VERSION 5.7 ;
BUSBITCHARS "[]" ;
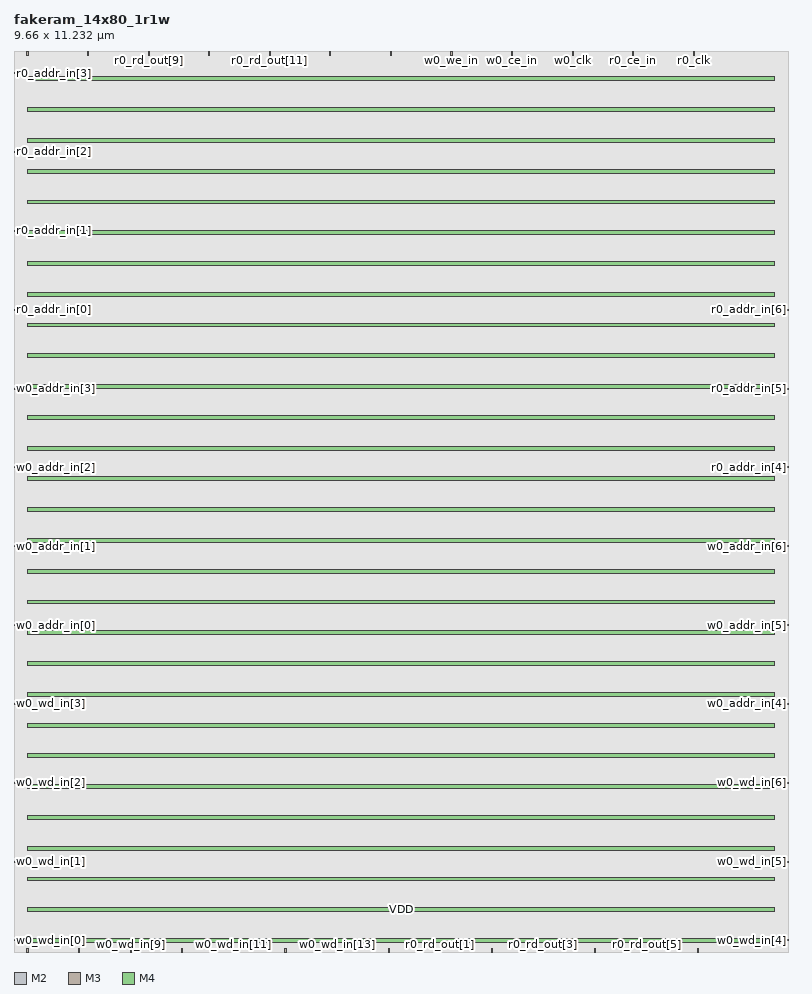
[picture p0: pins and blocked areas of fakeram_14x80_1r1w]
MACRO fakeram_14x80_1r1w
  FOREIGN fakeram_14x80_1r1w 0 0 ;
  SYMMETRY X Y R90 ;
  SIZE 9.660 BY 11.232 ;
  CLASS BLOCK ;
  PIN w0_wd_in[0]
    DIRECTION INPUT ;
    USE SIGNAL ;
    SHAPE ABUTMENT ;
    PORT
      LAYER M2 ;
      RECT 0.000 0.138 0.036 0.150 ;
    END
  END w0_wd_in[0]
  PIN w0_wd_in[1]
    DIRECTION INPUT ;
    USE SIGNAL ;
    SHAPE ABUTMENT ;
    PORT
      LAYER M2 ;
      RECT 0.000 1.122 0.036 1.134 ;
    END
  END w0_wd_in[1]
  PIN w0_wd_in[2]
    DIRECTION INPUT ;
    USE SIGNAL ;
    SHAPE ABUTMENT ;
    PORT
      LAYER M2 ;
      RECT 0.000 2.106 0.036 2.118 ;
    END
  END w0_wd_in[2]
  PIN w0_wd_in[3]
    DIRECTION INPUT ;
    USE SIGNAL ;
    SHAPE ABUTMENT ;
    PORT
      LAYER M2 ;
      RECT 0.000 3.090 0.036 3.102 ;
    END
  END w0_wd_in[3]
  PIN w0_wd_in[4]
    DIRECTION INPUT ;
    USE SIGNAL ;
    SHAPE ABUTMENT ;
    PORT
      LAYER M2 ;
      RECT 9.624 0.138 9.660 0.150 ;
    END
  END w0_wd_in[4]
  PIN w0_wd_in[5]
    DIRECTION INPUT ;
    USE SIGNAL ;
    SHAPE ABUTMENT ;
    PORT
      LAYER M2 ;
      RECT 9.624 1.122 9.660 1.134 ;
    END
  END w0_wd_in[5]
  PIN w0_wd_in[6]
    DIRECTION INPUT ;
    USE SIGNAL ;
    SHAPE ABUTMENT ;
    PORT
      LAYER M2 ;
      RECT 9.624 2.106 9.660 2.118 ;
    END
  END w0_wd_in[6]
  PIN w0_wd_in[7]
    DIRECTION INPUT ;
    USE SIGNAL ;
    SHAPE ABUTMENT ;
    PORT
      LAYER M3 ;
      RECT 0.161 0.000 0.175 0.042 ;
    END
  END w0_wd_in[7]
  PIN w0_wd_in[8]
    DIRECTION INPUT ;
    USE SIGNAL ;
    SHAPE ABUTMENT ;
    PORT
      LAYER M3 ;
      RECT 0.805 0.000 0.819 0.042 ;
    END
  END w0_wd_in[8]
  PIN w0_wd_in[9]
    DIRECTION INPUT ;
    USE SIGNAL ;
    SHAPE ABUTMENT ;
    PORT
      LAYER M3 ;
      RECT 1.449 0.000 1.463 0.042 ;
    END
  END w0_wd_in[9]
  PIN w0_wd_in[10]
    DIRECTION INPUT ;
    USE SIGNAL ;
    SHAPE ABUTMENT ;
    PORT
      LAYER M3 ;
      RECT 2.093 0.000 2.107 0.042 ;
    END
  END w0_wd_in[10]
  PIN w0_wd_in[11]
    DIRECTION INPUT ;
    USE SIGNAL ;
    SHAPE ABUTMENT ;
    PORT
      LAYER M3 ;
      RECT 2.737 0.000 2.751 0.042 ;
    END
  END w0_wd_in[11]
  PIN w0_wd_in[12]
    DIRECTION INPUT ;
    USE SIGNAL ;
    SHAPE ABUTMENT ;
    PORT
      LAYER M3 ;
      RECT 3.381 0.000 3.395 0.042 ;
    END
  END w0_wd_in[12]
  PIN w0_wd_in[13]
    DIRECTION INPUT ;
    USE SIGNAL ;
    SHAPE ABUTMENT ;
    PORT
      LAYER M3 ;
      RECT 4.025 0.000 4.039 0.042 ;
    END
  END w0_wd_in[13]
  PIN r0_rd_out[0]
    DIRECTION OUTPUT ;
    USE SIGNAL ;
    SHAPE ABUTMENT ;
    PORT
      LAYER M3 ;
      RECT 4.669 0.000 4.683 0.042 ;
    END
  END r0_rd_out[0]
  PIN r0_rd_out[1]
    DIRECTION OUTPUT ;
    USE SIGNAL ;
    SHAPE ABUTMENT ;
    PORT
      LAYER M3 ;
      RECT 5.313 0.000 5.327 0.042 ;
    END
  END r0_rd_out[1]
  PIN r0_rd_out[2]
    DIRECTION OUTPUT ;
    USE SIGNAL ;
    SHAPE ABUTMENT ;
    PORT
      LAYER M3 ;
      RECT 5.957 0.000 5.971 0.042 ;
    END
  END r0_rd_out[2]
  PIN r0_rd_out[3]
    DIRECTION OUTPUT ;
    USE SIGNAL ;
    SHAPE ABUTMENT ;
    PORT
      LAYER M3 ;
      RECT 6.601 0.000 6.615 0.042 ;
    END
  END r0_rd_out[3]
  PIN r0_rd_out[4]
    DIRECTION OUTPUT ;
    USE SIGNAL ;
    SHAPE ABUTMENT ;
    PORT
      LAYER M3 ;
      RECT 7.245 0.000 7.259 0.042 ;
    END
  END r0_rd_out[4]
  PIN r0_rd_out[5]
    DIRECTION OUTPUT ;
    USE SIGNAL ;
    SHAPE ABUTMENT ;
    PORT
      LAYER M3 ;
      RECT 7.889 0.000 7.903 0.042 ;
    END
  END r0_rd_out[5]
  PIN r0_rd_out[6]
    DIRECTION OUTPUT ;
    USE SIGNAL ;
    SHAPE ABUTMENT ;
    PORT
      LAYER M3 ;
      RECT 8.533 0.000 8.547 0.042 ;
    END
  END r0_rd_out[6]
  PIN r0_rd_out[7]
    DIRECTION OUTPUT ;
    USE SIGNAL ;
    SHAPE ABUTMENT ;
    PORT
      LAYER M3 ;
      RECT 0.161 11.190 0.175 11.232 ;
    END
  END r0_rd_out[7]
  PIN r0_rd_out[8]
    DIRECTION OUTPUT ;
    USE SIGNAL ;
    SHAPE ABUTMENT ;
    PORT
      LAYER M3 ;
      RECT 0.917 11.190 0.931 11.232 ;
    END
  END r0_rd_out[8]
  PIN r0_rd_out[9]
    DIRECTION OUTPUT ;
    USE SIGNAL ;
    SHAPE ABUTMENT ;
    PORT
      LAYER M3 ;
      RECT 1.673 11.190 1.687 11.232 ;
    END
  END r0_rd_out[9]
  PIN r0_rd_out[10]
    DIRECTION OUTPUT ;
    USE SIGNAL ;
    SHAPE ABUTMENT ;
    PORT
      LAYER M3 ;
      RECT 2.429 11.190 2.443 11.232 ;
    END
  END r0_rd_out[10]
  PIN r0_rd_out[11]
    DIRECTION OUTPUT ;
    USE SIGNAL ;
    SHAPE ABUTMENT ;
    PORT
      LAYER M3 ;
      RECT 3.185 11.190 3.199 11.232 ;
    END
  END r0_rd_out[11]
  PIN r0_rd_out[12]
    DIRECTION OUTPUT ;
    USE SIGNAL ;
    SHAPE ABUTMENT ;
    PORT
      LAYER M3 ;
      RECT 3.941 11.190 3.955 11.232 ;
    END
  END r0_rd_out[12]
  PIN r0_rd_out[13]
    DIRECTION OUTPUT ;
    USE SIGNAL ;
    SHAPE ABUTMENT ;
    PORT
      LAYER M3 ;
      RECT 4.697 11.190 4.711 11.232 ;
    END
  END r0_rd_out[13]
  PIN w0_addr_in[0]
    DIRECTION INPUT ;
    USE SIGNAL ;
    SHAPE ABUTMENT ;
    PORT
      LAYER M2 ;
      RECT 0.000 4.074 0.036 4.086 ;
    END
  END w0_addr_in[0]
  PIN w0_addr_in[1]
    DIRECTION INPUT ;
    USE SIGNAL ;
    SHAPE ABUTMENT ;
    PORT
      LAYER M2 ;
      RECT 0.000 5.058 0.036 5.070 ;
    END
  END w0_addr_in[1]
  PIN w0_addr_in[2]
    DIRECTION INPUT ;
    USE SIGNAL ;
    SHAPE ABUTMENT ;
    PORT
      LAYER M2 ;
      RECT 0.000 6.042 0.036 6.054 ;
    END
  END w0_addr_in[2]
  PIN w0_addr_in[3]
    DIRECTION INPUT ;
    USE SIGNAL ;
    SHAPE ABUTMENT ;
    PORT
      LAYER M2 ;
      RECT 0.000 7.026 0.036 7.038 ;
    END
  END w0_addr_in[3]
  PIN w0_addr_in[4]
    DIRECTION INPUT ;
    USE SIGNAL ;
    SHAPE ABUTMENT ;
    PORT
      LAYER M2 ;
      RECT 9.624 3.090 9.660 3.102 ;
    END
  END w0_addr_in[4]
  PIN w0_addr_in[5]
    DIRECTION INPUT ;
    USE SIGNAL ;
    SHAPE ABUTMENT ;
    PORT
      LAYER M2 ;
      RECT 9.624 4.074 9.660 4.086 ;
    END
  END w0_addr_in[5]
  PIN w0_addr_in[6]
    DIRECTION INPUT ;
    USE SIGNAL ;
    SHAPE ABUTMENT ;
    PORT
      LAYER M2 ;
      RECT 9.624 5.058 9.660 5.070 ;
    END
  END w0_addr_in[6]
  PIN r0_addr_in[0]
    DIRECTION INPUT ;
    USE SIGNAL ;
    SHAPE ABUTMENT ;
    PORT
      LAYER M2 ;
      RECT 0.000 8.010 0.036 8.022 ;
    END
  END r0_addr_in[0]
  PIN r0_addr_in[1]
    DIRECTION INPUT ;
    USE SIGNAL ;
    SHAPE ABUTMENT ;
    PORT
      LAYER M2 ;
      RECT 0.000 8.994 0.036 9.006 ;
    END
  END r0_addr_in[1]
  PIN r0_addr_in[2]
    DIRECTION INPUT ;
    USE SIGNAL ;
    SHAPE ABUTMENT ;
    PORT
      LAYER M2 ;
      RECT 0.000 9.978 0.036 9.990 ;
    END
  END r0_addr_in[2]
  PIN r0_addr_in[3]
    DIRECTION INPUT ;
    USE SIGNAL ;
    SHAPE ABUTMENT ;
    PORT
      LAYER M2 ;
      RECT 0.000 10.962 0.036 10.974 ;
    END
  END r0_addr_in[3]
  PIN r0_addr_in[4]
    DIRECTION INPUT ;
    USE SIGNAL ;
    SHAPE ABUTMENT ;
    PORT
      LAYER M2 ;
      RECT 9.624 6.042 9.660 6.054 ;
    END
  END r0_addr_in[4]
  PIN r0_addr_in[5]
    DIRECTION INPUT ;
    USE SIGNAL ;
    SHAPE ABUTMENT ;
    PORT
      LAYER M2 ;
      RECT 9.624 7.026 9.660 7.038 ;
    END
  END r0_addr_in[5]
  PIN r0_addr_in[6]
    DIRECTION INPUT ;
    USE SIGNAL ;
    SHAPE ABUTMENT ;
    PORT
      LAYER M2 ;
      RECT 9.624 8.010 9.660 8.022 ;
    END
  END r0_addr_in[6]
  PIN w0_we_in
    DIRECTION INPUT ;
    USE SIGNAL ;
    SHAPE ABUTMENT ;
    PORT
      LAYER M3 ;
      RECT 5.453 11.190 5.467 11.232 ;
    END
  END w0_we_in
  PIN w0_ce_in
    DIRECTION INPUT ;
    USE SIGNAL ;
    SHAPE ABUTMENT ;
    PORT
      LAYER M3 ;
      RECT 6.209 11.190 6.223 11.232 ;
    END
  END w0_ce_in
  PIN w0_clk
    DIRECTION INPUT ;
    USE SIGNAL ;
    SHAPE ABUTMENT ;
    PORT
      LAYER M3 ;
      RECT 6.965 11.190 6.979 11.232 ;
    END
  END w0_clk
  PIN r0_ce_in
    DIRECTION INPUT ;
    USE SIGNAL ;
    SHAPE ABUTMENT ;
    PORT
      LAYER M3 ;
      RECT 7.721 11.190 7.735 11.232 ;
    END
  END r0_ce_in
  PIN r0_clk
    DIRECTION INPUT ;
    USE SIGNAL ;
    SHAPE ABUTMENT ;
    PORT
      LAYER M3 ;
      RECT 8.477 11.190 8.491 11.232 ;
    END
  END r0_clk
  PIN VSS
    DIRECTION INOUT ;
    USE GROUND ;
    PORT
      LAYER M4 ;
      RECT 0.168 0.120 9.492 0.168 ;
      RECT 0.168 0.504 9.492 0.552 ;
      RECT 0.168 0.888 9.492 0.936 ;
      RECT 0.168 1.272 9.492 1.320 ;
      RECT 0.168 1.656 9.492 1.704 ;
      RECT 0.168 2.040 9.492 2.088 ;
      RECT 0.168 2.424 9.492 2.472 ;
      RECT 0.168 2.808 9.492 2.856 ;
      RECT 0.168 3.192 9.492 3.240 ;
      RECT 0.168 3.576 9.492 3.624 ;
      RECT 0.168 3.960 9.492 4.008 ;
      RECT 0.168 4.344 9.492 4.392 ;
      RECT 0.168 4.728 9.492 4.776 ;
      RECT 0.168 5.112 9.492 5.160 ;
      RECT 0.168 5.496 9.492 5.544 ;
      RECT 0.168 5.880 9.492 5.928 ;
      RECT 0.168 6.264 9.492 6.312 ;
      RECT 0.168 6.648 9.492 6.696 ;
      RECT 0.168 7.032 9.492 7.080 ;
      RECT 0.168 7.416 9.492 7.464 ;
      RECT 0.168 7.800 9.492 7.848 ;
      RECT 0.168 8.184 9.492 8.232 ;
      RECT 0.168 8.568 9.492 8.616 ;
      RECT 0.168 8.952 9.492 9.000 ;
      RECT 0.168 9.336 9.492 9.384 ;
      RECT 0.168 9.720 9.492 9.768 ;
      RECT 0.168 10.104 9.492 10.152 ;
      RECT 0.168 10.488 9.492 10.536 ;
      RECT 0.168 10.872 9.492 10.920 ;
    END
  END VSS
  PIN VDD
    DIRECTION INOUT ;
    USE POWER ;
    PORT
      LAYER M4 ;
      RECT 0.168 0.120 9.492 0.168 ;
      RECT 0.168 0.504 9.492 0.552 ;
      RECT 0.168 0.888 9.492 0.936 ;
      RECT 0.168 1.272 9.492 1.320 ;
      RECT 0.168 1.656 9.492 1.704 ;
      RECT 0.168 2.040 9.492 2.088 ;
      RECT 0.168 2.424 9.492 2.472 ;
      RECT 0.168 2.808 9.492 2.856 ;
      RECT 0.168 3.192 9.492 3.240 ;
      RECT 0.168 3.576 9.492 3.624 ;
      RECT 0.168 3.960 9.492 4.008 ;
      RECT 0.168 4.344 9.492 4.392 ;
      RECT 0.168 4.728 9.492 4.776 ;
      RECT 0.168 5.112 9.492 5.160 ;
      RECT 0.168 5.496 9.492 5.544 ;
      RECT 0.168 5.880 9.492 5.928 ;
      RECT 0.168 6.264 9.492 6.312 ;
      RECT 0.168 6.648 9.492 6.696 ;
      RECT 0.168 7.032 9.492 7.080 ;
      RECT 0.168 7.416 9.492 7.464 ;
      RECT 0.168 7.800 9.492 7.848 ;
      RECT 0.168 8.184 9.492 8.232 ;
      RECT 0.168 8.568 9.492 8.616 ;
      RECT 0.168 8.952 9.492 9.000 ;
      RECT 0.168 9.336 9.492 9.384 ;
      RECT 0.168 9.720 9.492 9.768 ;
      RECT 0.168 10.104 9.492 10.152 ;
      RECT 0.168 10.488 9.492 10.536 ;
      RECT 0.168 10.872 9.492 10.920 ;
    END
  END VDD
  OBS
    LAYER M1 ;
    RECT 0 0 9.660 11.232 ;
    LAYER M2 ;
    RECT 0 0 9.660 11.232 ;
    LAYER M3 ;
    RECT 0 0 9.660 11.232 ;
    LAYER M4 ;
    RECT 0 0 9.660 11.232 ;
  END
END fakeram_14x80_1r1w

END LIBRARY
